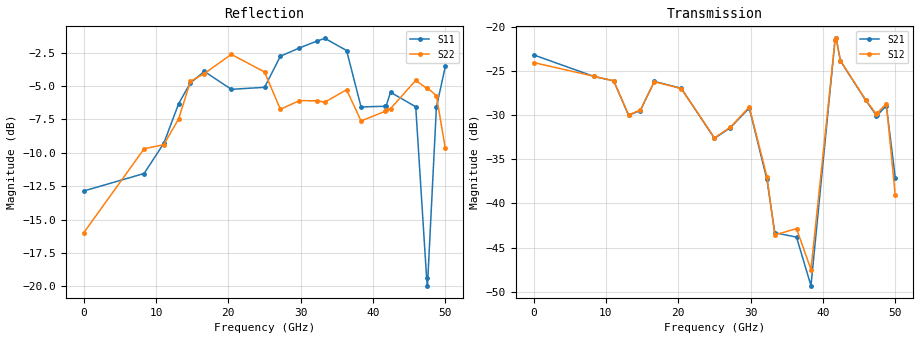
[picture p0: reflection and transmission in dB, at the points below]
!Keysight Technologies,N5245B,MY58422270,A.16.20.02
!Date: Thursday, March 05, 2026 01:28:48
!Correction: S11(C  2-Port  )
!S21(C  2-Port  )
!S12(C  2-Port  )
!S22(C  2-Port  )
!S2P File: Measurements: S11, S21, S12, S22:
# Hz S  dB  R 50
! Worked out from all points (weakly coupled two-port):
!   3201 points, 10 MHz to 50 GHz, reference 50 ohm
!   highest |S21| = -21.34 dB at 41.83 GHz (marker M1); lowest = -49.3 dB at 38.35 GHz (marker M2)
!   lowest |S11| = -20.0 dB at 47.53 GHz (marker M3), VSWR 1.22, Z = 45.9 + j8.79 ohm
!   |S11| at or under -10 dB: start of sweep to 10.09 GHz; 11.36 GHz to 11.92 GHz (558 MHz wide, 4.79 % of centre); 46.66 GHz to 48.29 GHz (1.629 GHz wide, 3.43 % of centre)
!   |S22| runs from -21.2 to -2.6 dB; largest |S21 - S12| = 0.0096
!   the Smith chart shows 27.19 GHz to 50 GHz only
!   S11 on the Smith chart (normalised r, x): 27.19 GHz: 0.18, +0.36; 32.25 GHz: 0.41, +1.82; 36.35 GHz: 2.44, -3.42; 42.42 GHz: 1.01, -1.27; 47.41 GHz: 0.84, +0.12; 50 GHz: 0.61, -1.35
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1e7  -12.86 -3.7  -23.21 5.9  -24.08 -0.2  -15.99 39.3
8.352081e9  -11.55 175.1  -25.65 30.0  -25.63 30.0  -9.70 -173.6
1.107029e10  -9.29 109.8  -26.15 -71.9  -26.14 -71.8  -9.39 85.3
1.313238e10  -6.31 65.2  -30.03 -130.2  -29.98 -130.1  -7.45 -22.1
1.475705e10  -4.75 13.3  -29.50 -152.3  -29.46 -152.3  -4.64 -90.5
1.667854e10  -3.90 -43.8  -26.21 157.6  -26.24 157.7  -4.06 -141.0
2.041217e10  -5.24 -121.7  -26.99 39.3  -27.01 39.1  -2.62 155.1
2.5005e10  -5.09 179.8  -32.65 -65.8  -32.58 -66.4  -3.94 71.6
2.719206e10  -2.76 139.5  -31.45 -114.2  -31.39 -113.2  -6.74 32.4
2.981654e10  -2.14 94.0  -29.22 159.2  -29.09 159.4  -6.09 -28.2
3.225355e10  -1.62 55.6  -37.27 49.0  -36.96 52.4  -6.10 -102.4
3.334708e10  -1.42 36.1  -43.31 7.0  -43.56 2.7  -6.20 -126.5
3.634648e10  -2.33 -22.3  -43.81 119.1  -42.85 114.6  -5.27 174.4
3.834608e10  -6.56 -22.2  -49.30 -90.0  -47.47 -100.5  -7.61 141.2
4.167354e10  -6.51 -52.6  -21.54 -54.5  -21.55 -54.9  -6.89 115.3
4.182976e10  -6.47 -52.5  -21.34 -69.2  -21.34 -69.5  -6.76 113.9
4.242339e10  -5.46 -57.2  -23.90 -114.4  -23.86 -113.9  -6.69 109.9
4.590707e10  -6.55 -117.7  -28.34 50.1  -28.29 48.8  -4.57 62.2
4.740677e10  -19.35 138.5  -30.07 0.7  -29.94 -1.4  -5.16 43.0
4.753174e10  -19.96 109.6  -30.02 -0.7  -29.78 -3.3  -5.13 41.7
4.876587e10  -6.58 -24.0  -28.95 -90.1  -28.71 -90.5  -5.73 17.7
5e10  -3.52 -66.1  -37.08 -136.3  -39.07 -127.2  -9.67 3.9
